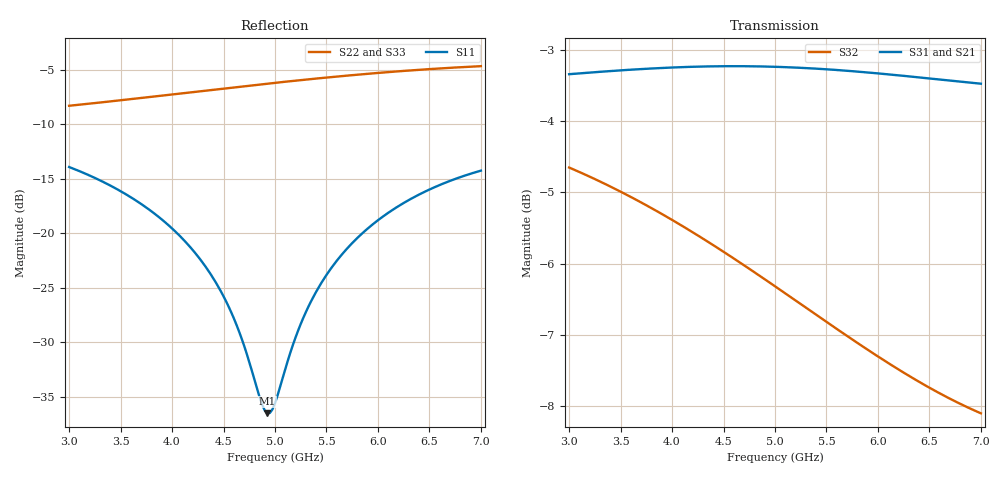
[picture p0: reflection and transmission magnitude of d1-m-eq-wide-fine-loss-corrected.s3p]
! yapnr Order 0 prediction d1-m-eq-wide-fine: predictions/D1/variants/d1-star-m-eq/fine.s3p, loss-corrected
! substrate M-eq; coupon model OSHPARK-4L-FR408HR; correction: ratio (port line)
! |S21|, |S31| (and S12, S13) scaled, phases kept; 50 ohm, e^(+jwt)
# GHz S RI R 50
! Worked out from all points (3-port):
!   161 points, 3 GHz to 7 GHz, reference 50 ohm
!   strongest paths, dB at 3 GHz, 4 GHz, 5 GHz, 6 GHz, 7 GHz:
!     S31: -3.3, -3.2, -3.2, -3.3, -3.5
!     S21: -3.3, -3.2, -3.2, -3.3, -3.5
!     S32: -4.7, -5.4, -6.3, -7.3, -8.1
!   lowest |S11| = -36.5 dB at 4.925 GHz (marker M1), VSWR 1.03, Z = 48.6 + j0.34 ohm
!   |S11| at or under -10 dB: start of sweep to end of sweep
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3  -0.1215 0.1608  0.1061 -0.6722  0.1061 -0.6722
   0.106 -0.6722  0.0919 0.3738  -0.1491 -0.566
   0.106 -0.6722  -0.1491 -0.566  0.0919 0.3738
3.7  -0.0566 0.1241  -0.1271 -0.6744  -0.1271 -0.6744
     -0.1271 -0.6743  0.2538 0.3322  -0.3436 -0.4336
     -0.1271 -0.6743  -0.3436 -0.4336  0.2538 0.3322
4.225  -0.0242 0.0776  -0.2975 -0.6213  -0.2975 -0.6213
       -0.2975 -0.6212  0.3642 0.2579  -0.4341 -0.297
       -0.2975 -0.6212  -0.4341 -0.297  0.3642 0.2579
4.575  -0.0141 0.0411  -0.4013 -0.5607  -0.4013 -0.5607
       -0.4013 -0.5606  0.4259 0.1894  -0.4658 -0.1997
       -0.4013 -0.5606  -0.4658 -0.1997  0.4259 0.1894
4.925  -0.0145 0.0035  -0.4925 -0.4819  -0.4925 -0.4819
       -0.4924 -0.4818  0.4741 0.1079  -0.4761 -0.1041
       -0.4924 -0.4818  -0.4761 -0.1041  0.4741 0.1079
5  -0.016 -0.00439  -0.51 -0.4629  -0.51 -0.4629
   -0.51 -0.4628  0.4824 0.089  -0.4758 -0.0843
   -0.51 -0.4628  -0.4758 -0.0843  0.4824 0.089
5.3  -0.0269 -0.0342  -0.5723 -0.3807  -0.5723 -0.3807
     -0.5722 -0.3807  0.5075 0.0097  -0.4668 -0.00857
     -0.5722 -0.3807  -0.4668 -0.00857  0.5075 0.0097
5.675  -0.0503 -0.0655  -0.6305 -0.2667  -0.6305 -0.2667
       -0.6305 -0.2666  0.5194 -0.0951  -0.4407 0.0763
       -0.6305 -0.2666  -0.4407 0.0763  0.5194 -0.0951
6.25  -0.1016 -0.0932  -0.6743 -0.0783  -0.6743 -0.0783
      -0.6742 -0.0783  0.4938 -0.2562  -0.3789 0.1821
      -0.6742 -0.0783  -0.3789 0.1821  0.4938 -0.2562
7  -0.1753 -0.0831  -0.6494 0.166  -0.6494 0.166
   -0.6493 0.166  0.3871 -0.4385  -0.2783 0.2784
   -0.6493 0.166  -0.2783 0.2784  0.3871 -0.4385
